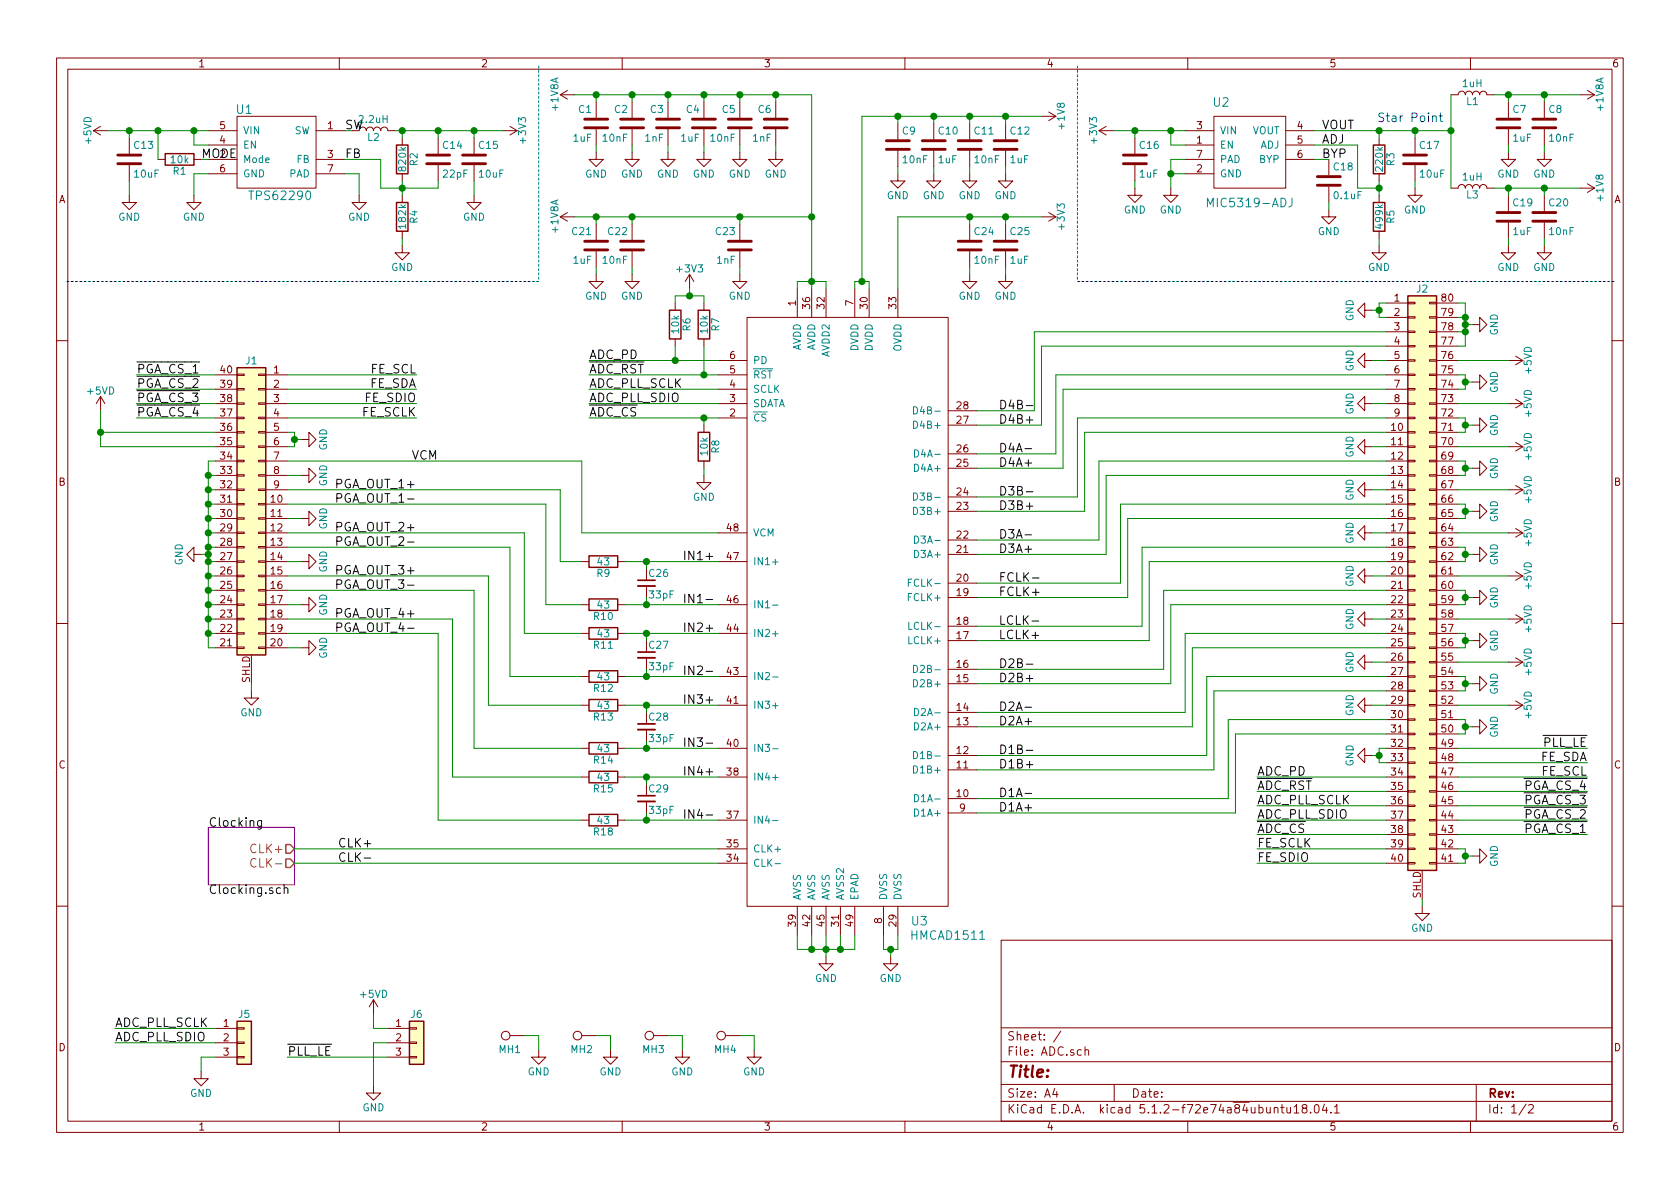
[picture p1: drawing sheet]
<svg xmlns="http://www.w3.org/2000/svg" width="297mm" height="210mm" viewBox="0 0 297 210" stroke-linecap="round" stroke-linejoin="round" font-family="sans-serif">
<defs><g id="words">
<text font-size="2.8" fill="#840000" x="178" y="190.5">Title:</text>
<g font-size="2.1" fill="#008484">
<text x="41.8" y="20.1">U1</text>
<text x="214.6" y="18.9">U2</text>
<text x="44.5" y="35.4">TPS62290</text>
<text x="214.2" y="36.6">MIC5319-ADJ</text>
<text x="161.2" y="163.6">U3</text>
<text x="161.3" y="166.2">HMCAD1511</text>
</g>
<g font-size="2.1" fill="#008400">
<text x="61" y="22.9">SW</text>
<text x="35.6" y="27.9">MODE</text>
</g>
<g font-size="2.1">
<text x="233.7" y="22.9">VOUT</text>
<text x="61" y="27.9">FB</text>
<text x="233.7" y="25.4">ADJ</text>
<text x="233.7" y="27.9">BYP</text>
<text x="104.1" y="63.5">ADC_PD</text>
<text x="24.1" y="66">PGA_CS_1</text>
<text x="24.1" y="68.6">PGA_CS_2</text>
<text x="24.1" y="71.1">PGA_CS_3</text>
<text x="64.6" y="71.1">FE_SDIO</text>
<text x="65.3" y="68.6">FE_SDA</text>
<text x="65.5" y="66">FE_SCL</text>
<text x="104.1" y="71.1">ADC_PLL_SDIO</text>
<text x="104.1" y="68.6">ADC_PLL_SCLK</text>
<text x="104.1" y="66">ADC_RST</text>
<text x="24.1" y="73.7">PGA_CS_4</text>
<text x="64" y="73.7">FE_SCLK</text>
<text x="104.1" y="73.7">ADC_CS</text>
<text x="176.5" y="72.4">D4B-</text>
<text x="176.5" y="74.9">D4B+</text>
<text x="72.7" y="81.3">VCM</text>
<text x="176.5" y="80">D4A-</text>
<text x="176.5" y="82.5">D4A+</text>
<text x="59.8" y="86.4">PGA_OUT_1+</text>
<text x="60.3" y="88.9">PGA_OUT_1-</text>
<text x="176.5" y="87.6">D3B-</text>
<text x="59.8" y="94">PGA_OUT_2+</text>
<text x="176.5" y="95.2">D3A-</text>
<text x="176.5" y="90.2">D3B+</text>
<text x="59.8" y="101.6">PGA_OUT_3+</text>
<text x="60.3" y="96.5">PGA_OUT_2-</text>
<text x="120.6" y="99.1">IN1+</text>
<text x="176.5" y="97.8">D3A+</text>
<text x="60.3" y="104.1">PGA_OUT_3-</text>
<text x="120.6" y="106.7">IN1-</text>
<text x="176.5" y="102.9">FCLK-</text>
<text x="176.5" y="105.4">FCLK+</text>
<text x="59.8" y="109.2">PGA_OUT_4+</text>
<text x="60.3" y="111.8">PGA_OUT_4-</text>
<text x="120.6" y="111.8">IN2+</text>
<text x="176.5" y="113">LCLK+</text>
<text x="176.5" y="110.5">LCLK-</text>
<text x="120.6" y="119.4">IN2-</text>
<text x="176.5" y="118.1">D2B-</text>
<text x="120.6" y="124.5">IN3+</text>
<text x="176.5" y="125.7">D2A-</text>
<text x="176.5" y="120.6">D2B+</text>
<text x="176.5" y="128.3">D2A+</text>
<text x="120.6" y="137.2">IN4+</text>
<text x="120.6" y="132.1">IN3-</text>
<text x="176.5" y="135.9">D1B+</text>
<text x="176.5" y="133.3">D1B-</text>
<text x="222.2" y="137.2">ADC_PD</text>
<text x="272.3" y="134.6">FE_SDA</text>
<text x="272.5" y="137.2">FE_SCL</text>
<text x="272.8" y="132.1">PLL_LE</text>
<text x="176.5" y="143.5">D1A+</text>
<text x="176.5" y="141">D1A-</text>
<text x="222.2" y="139.7">ADC_RST</text>
<text x="222.2" y="142.2">ADC_PLL_SCLK</text>
<text x="269.6" y="142.2">PGA_CS_3</text>
<text x="269.6" y="139.7">PGA_CS_4</text>
<text x="36.8" y="146.2">Clocking</text>
<text x="59.7" y="149.9">CLK+</text>
<text x="120.6" y="144.8">IN4-</text>
<text x="222.2" y="144.8">ADC_PLL_SDIO</text>
<text x="222.2" y="147.3">ADC_CS</text>
<text x="222.2" y="149.9">FE_SCLK</text>
<text x="269.6" y="147.3">PGA_CS_1</text>
<text x="269.6" y="144.8">PGA_CS_2</text>
<text x="59.7" y="152.4">CLK-</text>
<text x="222.2" y="152.4">FE_SDIO</text>
<text x="36.8" y="158.1">Clocking.sch</text>
<text x="20.3" y="184.1">ADC_PLL_SDIO</text>
<text x="20.3" y="181.6">ADC_PLL_SCLK</text>
<text x="50.8" y="186.7">PLL_LE</text>
</g>
<text font-size="2.1" fill="#0000c2" x="245.2" y="21.6">Star Point</text>
<g font-size="2.1" fill="#848400">
<text x="44.7" y="150.9">CLK+</text>
<text x="45.2" y="153.4">CLK-</text>
</g>
<g font-size="2.1" fill="#840000">
<text x="178" y="184">Sheet: /</text>
<text x="178" y="186.7">File: ADC.sch</text>
<text x="178" y="196.9">KiCad E.D.A. kicad 5.1.2-f72e74a84ubuntu18.04.1</text>
<text x="178" y="194.1">Size: A4</text>
<text x="200" y="194.1">Date:</text>
<text x="263" y="194.1">Rev:</text>
<text x="263" y="196.9">Id: 1/2</text>
</g>
<g font-size="1.8" fill="#840000">
<text x="35" y="11.9">1</text>
<text x="85" y="11.9">2</text>
<text x="135" y="11.9">3</text>
<text x="185" y="11.9">4</text>
<text x="235" y="11.9">5</text>
<text x="285" y="11.9">6</text>
<text x="38.9" y="22.9">5</text>
<text x="57.9" y="22.9">1</text>
<text x="211.6" y="22.9">3</text>
<text x="229.4" y="22.9">4</text>
<text x="38.9" y="25.4">4</text>
<text x="57.9" y="27.9">3</text>
<text x="211.6" y="25.4">1</text>
<text x="211.6" y="27.9">7</text>
<text x="229.4" y="25.4">5</text>
<text x="229.4" y="27.9">6</text>
<text x="10.4" y="35.9">A</text>
<text x="38.9" y="30.5">6</text>
<text x="57.9" y="30.5">7</text>
<text x="211.6" y="30.5">2</text>
<text x="285.4" y="35.9">A</text>
<text x="246.5" y="53.3">1</text>
<text x="254.9" y="53.3">80</text>
<text x="140.7" y="54.1" transform="rotate(-90 140.7 54.1)">1</text>
<text x="143.3" y="54.6" transform="rotate(-90 143.3 54.6)">36</text>
<text x="145.8" y="54.6" transform="rotate(-90 145.8 54.6)">32</text>
<text x="150.9" y="54.1" transform="rotate(-90 150.9 54.1)">7</text>
<text x="153.4" y="54.6" transform="rotate(-90 153.4 54.6)">30</text>
<text x="158.5" y="54.6" transform="rotate(-90 158.5 54.6)">33</text>
<text x="246.5" y="55.9">2</text>
<text x="246.5" y="58.4">3</text>
<text x="254.9" y="58.4">78</text>
<text x="254.9" y="55.9">79</text>
<text x="129.1" y="63.5">6</text>
<text x="246.5" y="61">4</text>
<text x="246.5" y="63.5">5</text>
<text x="254.9" y="63.5">76</text>
<text x="254.9" y="61">77</text>
<text x="39" y="71.1">38</text>
<text x="39" y="68.6">39</text>
<text x="39" y="66">40</text>
<text x="48.4" y="66">1</text>
<text x="48.4" y="68.6">2</text>
<text x="48.4" y="71.1">3</text>
<text x="129.1" y="71.1">3</text>
<text x="129.1" y="68.6">4</text>
<text x="129.1" y="66">5</text>
<text x="246.5" y="66">6</text>
<text x="246.5" y="68.6">7</text>
<text x="246.5" y="71.1">8</text>
<text x="254.9" y="71.1">73</text>
<text x="254.9" y="68.6">74</text>
<text x="254.9" y="66">75</text>
<text x="39" y="76.2">36</text>
<text x="39" y="73.7">37</text>
<text x="48.4" y="73.7">4</text>
<text x="48.4" y="76.2">5</text>
<text x="129.1" y="73.7">2</text>
<text x="169.2" y="74.9">27</text>
<text x="169.2" y="72.4">28</text>
<text x="246" y="76.2">10</text>
<text x="246.5" y="73.7">9</text>
<text x="254.9" y="76.2">71</text>
<text x="254.9" y="73.7">72</text>
<text x="39" y="83.8">33</text>
<text x="39" y="81.3">34</text>
<text x="39" y="78.7">35</text>
<text x="48.4" y="78.7">6</text>
<text x="48.4" y="81.3">7</text>
<text x="48.4" y="83.8">8</text>
<text x="169.2" y="82.5">25</text>
<text x="169.2" y="80">26</text>
<text x="246" y="78.7">11</text>
<text x="246" y="81.3">12</text>
<text x="246" y="83.8">13</text>
<text x="254.9" y="83.8">68</text>
<text x="254.9" y="81.3">69</text>
<text x="254.9" y="78.7">70</text>
<text x="10.4" y="85.9">B</text>
<text x="39" y="88.9">31</text>
<text x="39" y="86.4">32</text>
<text x="47.9" y="88.9">10</text>
<text x="48.4" y="86.4">9</text>
<text x="169.2" y="87.6">24</text>
<text x="246" y="86.4">14</text>
<text x="246" y="88.9">15</text>
<text x="254.9" y="88.9">66</text>
<text x="254.9" y="86.4">67</text>
<text x="285.4" y="85.9">B</text>
<text x="39" y="94">29</text>
<text x="39" y="91.4">30</text>
<text x="47.9" y="91.4">11</text>
<text x="47.9" y="94">12</text>
<text x="128.6" y="94">48</text>
<text x="169.2" y="95.2">22</text>
<text x="169.2" y="90.2">23</text>
<text x="246" y="91.4">16</text>
<text x="246" y="94">17</text>
<text x="254.9" y="94">64</text>
<text x="254.9" y="91.4">65</text>
<text x="39" y="101.6">26</text>
<text x="39" y="99.1">27</text>
<text x="39" y="96.5">28</text>
<text x="47.9" y="96.5">13</text>
<text x="47.9" y="99.1">14</text>
<text x="47.9" y="101.6">15</text>
<text x="128.6" y="99.1">47</text>
<text x="169.2" y="97.8">21</text>
<text x="246" y="96.5">18</text>
<text x="246" y="99.1">19</text>
<text x="246" y="101.6">20</text>
<text x="254.9" y="101.6">61</text>
<text x="254.9" y="99.1">62</text>
<text x="254.9" y="96.5">63</text>
<text x="39" y="106.7">24</text>
<text x="39" y="104.1">25</text>
<text x="47.9" y="104.1">16</text>
<text x="47.9" y="106.7">17</text>
<text x="128.6" y="106.7">46</text>
<text x="169.2" y="105.4">19</text>
<text x="169.2" y="102.9">20</text>
<text x="246" y="104.1">21</text>
<text x="246" y="106.7">22</text>
<text x="254.9" y="106.7">59</text>
<text x="254.9" y="104.1">60</text>
<text x="39" y="111.8">22</text>
<text x="39" y="109.2">23</text>
<text x="47.9" y="109.2">18</text>
<text x="47.9" y="111.8">19</text>
<text x="128.6" y="111.8">44</text>
<text x="169.2" y="113">17</text>
<text x="169.2" y="110.5">18</text>
<text x="246" y="109.2">23</text>
<text x="246" y="111.8">24</text>
<text x="254.9" y="111.8">57</text>
<text x="254.9" y="109.2">58</text>
<text x="39" y="114.3">21</text>
<text x="47.9" y="114.3">20</text>
<text x="128.6" y="119.4">43</text>
<text x="169.2" y="118.1">16</text>
<text x="246" y="114.3">25</text>
<text x="246" y="116.8">26</text>
<text x="246" y="119.4">27</text>
<text x="254.9" y="119.4">54</text>
<text x="254.9" y="116.8">55</text>
<text x="254.9" y="114.3">56</text>
<text x="44.2" y="120.8" transform="rotate(-90 44.2 120.8)">SHLD</text>
<text x="128.6" y="124.5">41</text>
<text x="169.2" y="125.7">14</text>
<text x="169.2" y="120.6">15</text>
<text x="246" y="121.9">28</text>
<text x="246" y="124.5">29</text>
<text x="254.9" y="124.5">52</text>
<text x="254.9" y="121.9">53</text>
<text x="169.2" y="128.3">13</text>
<text x="246" y="127">30</text>
<text x="246" y="129.5">31</text>
<text x="254.9" y="129.5">50</text>
<text x="254.9" y="127">51</text>
<text x="10.4" y="135.9">C</text>
<text x="128.6" y="137.2">38</text>
<text x="128.6" y="132.1">40</text>
<text x="169.2" y="135.9">11</text>
<text x="169.2" y="133.3">12</text>
<text x="246" y="132.1">32</text>
<text x="246" y="134.6">33</text>
<text x="246" y="137.2">34</text>
<text x="254.9" y="137.2">47</text>
<text x="254.9" y="134.6">48</text>
<text x="254.9" y="132.1">49</text>
<text x="285.4" y="135.9">C</text>
<text x="169.2" y="141">10</text>
<text x="169.7" y="143.5">9</text>
<text x="246" y="139.7">35</text>
<text x="246" y="142.2">36</text>
<text x="254.9" y="142.2">45</text>
<text x="254.9" y="139.7">46</text>
<text x="128.6" y="149.9">35</text>
<text x="128.6" y="144.8">37</text>
<text x="246" y="144.8">37</text>
<text x="246" y="147.3">38</text>
<text x="246" y="149.9">39</text>
<text x="254.9" y="149.9">42</text>
<text x="254.9" y="147.3">43</text>
<text x="254.9" y="144.8">44</text>
<text x="128.6" y="152.4">34</text>
<text x="246" y="152.4">40</text>
<text x="254.9" y="152.4">41</text>
<text x="251.2" y="158.9" transform="rotate(-90 251.2 158.9)">SHLD</text>
<text x="140.7" y="163.8" transform="rotate(-90 140.7 163.8)">39</text>
<text x="143.3" y="163.8" transform="rotate(-90 143.3 163.8)">42</text>
<text x="145.8" y="163.8" transform="rotate(-90 145.8 163.8)">45</text>
<text x="148.3" y="163.8" transform="rotate(-90 148.3 163.8)">31</text>
<text x="150.9" y="163.8" transform="rotate(-90 150.9 163.8)">49</text>
<text x="156" y="163.3" transform="rotate(-90 156 163.3)">8</text>
<text x="158.5" y="163.8" transform="rotate(-90 158.5 163.8)">29</text>
<text x="10.4" y="185.9">D</text>
<text x="39.5" y="181.6">1</text>
<text x="39.5" y="184.1">2</text>
<text x="70" y="181.6">1</text>
<text x="70" y="184.1">2</text>
<text x="285.4" y="185.9">D</text>
<text x="39.5" y="186.7">3</text>
<text x="70" y="186.7">3</text>
<text x="35" y="199.9">1</text>
<text x="85" y="199.9">2</text>
<text x="135" y="199.9">3</text>
<text x="185" y="199.9">4</text>
<text x="235" y="199.9">5</text>
<text x="285" y="199.9">6</text>
</g>
<g font-size="1.8" fill="#008484">
<text x="258.6" y="15.4">1uH</text>
<text x="42.9" y="23.7">VIN</text>
<text x="52" y="23.7">SW</text>
<text x="63.6" y="21.8">2.2uH</text>
<text x="98.7" y="19.5" transform="rotate(-90 98.7 19.5)">+1V8A</text>
<text x="102.3" y="20">C1</text>
<text x="108.7" y="20">C2</text>
<text x="115" y="20">C3</text>
<text x="121.4" y="20">C4</text>
<text x="127.7" y="20">C5</text>
<text x="134.1" y="20">C6</text>
<text x="159.6" y="23.8">C9</text>
<text x="166" y="23.8">C10</text>
<text x="172.4" y="23.8">C11</text>
<text x="178.7" y="23.8">C12</text>
<text x="188.3" y="22.7" transform="rotate(-90 188.3 22.7)">+1V8</text>
<text x="215.6" y="23.7">VIN</text>
<text x="221.4" y="23.7">VOUT</text>
<text x="259.3" y="18.6">L1</text>
<text x="267.5" y="20">C7</text>
<text x="273.9" y="20">C8</text>
<text x="283.5" y="19.5" transform="rotate(-90 283.5 19.5)">+1V8A</text>
<text x="16.2" y="25.3" transform="rotate(-90 16.2 25.3)">+5VD</text>
<text x="23.8" y="26.3">C13</text>
<text x="30.3" y="28.9">10k</text>
<text x="42.9" y="28.8">Mode</text>
<text x="42.9" y="26.3">EN</text>
<text x="52.5" y="28.8">FB</text>
<text x="65" y="24.9">L2</text>
<text x="73.8" y="29.3" transform="rotate(-90 73.8 29.3)">R2</text>
<text x="78.4" y="26.3">C14</text>
<text x="84.7" y="26.3">C15</text>
<text x="93" y="25.2" transform="rotate(-90 93 25.2)">+3V3</text>
<text x="101.4" y="25.1">1uF</text>
<text x="106.7" y="25.1">10nF</text>
<text x="114.1" y="25.1">1nF</text>
<text x="120.4" y="25.1">1uF</text>
<text x="125.7" y="25.1">10nF</text>
<text x="133.1" y="25.1">1nF</text>
<text x="159.7" y="28.9">10nF</text>
<text x="166" y="28.9">1uF</text>
<text x="172.4" y="28.9">10nF</text>
<text x="178.7" y="28.9">1uF</text>
<text x="194" y="25.2" transform="rotate(-90 194 25.2)">+3V3</text>
<text x="201.6" y="26.3">C16</text>
<text x="215.6" y="26.3">EN</text>
<text x="215.6" y="28.8">PAD</text>
<text x="222.7" y="28.8">BYP</text>
<text x="222.8" y="26.3">ADJ</text>
<text x="246.6" y="29.3" transform="rotate(-90 246.6 29.3)">R3</text>
<text x="251.1" y="26.3">C17</text>
<text x="267.6" y="25.1">1uF</text>
<text x="274" y="25.1">10nF</text>
<text x="23.8" y="31.4">10uF</text>
<text x="30.6" y="30.9">R1</text>
<text x="42.9" y="31.4">GND</text>
<text x="51.1" y="31.4">PAD</text>
<text x="71.8" y="30.1" transform="rotate(-90 71.8 30.1)">820k</text>
<text x="78.4" y="31.4">22pF</text>
<text x="84.8" y="31.4">10uF</text>
<text x="103.5" y="31.4">GND</text>
<text x="109.8" y="31.4">GND</text>
<text x="116.2" y="31.4">GND</text>
<text x="122.5" y="31.4">GND</text>
<text x="128.9" y="31.4">GND</text>
<text x="135.2" y="31.4">GND</text>
<text x="156.8" y="35.2">GND</text>
<text x="163.1" y="35.2">GND</text>
<text x="169.5" y="35.2">GND</text>
<text x="175.8" y="35.2">GND</text>
<text x="201.5" y="31.4">1uF</text>
<text x="215.6" y="31.4">GND</text>
<text x="235.9" y="30.1">C18</text>
<text x="236" y="35.2">0.1uF</text>
<text x="244.5" y="30.1" transform="rotate(-90 244.5 30.1)">220k</text>
<text x="251.2" y="31.4">10uF</text>
<text x="258.6" y="31.9">1uH</text>
<text x="259.3" y="35.1">L3</text>
<text x="264.7" y="31.4">GND</text>
<text x="271.1" y="31.4">GND</text>
<text x="283.5" y="35.4" transform="rotate(-90 283.5 35.4)">+1V8</text>
<text x="20.9" y="39">GND</text>
<text x="32.3" y="39">GND</text>
<text x="61.5" y="39">GND</text>
<text x="71.8" y="40.3" transform="rotate(-90 71.8 40.3)">182k</text>
<text x="73.8" y="39.5" transform="rotate(-90 73.8 39.5)">R4</text>
<text x="81.9" y="39">GND</text>
<text x="98.7" y="41" transform="rotate(-90 98.7 41)">+1V8A</text>
<text x="101.2" y="41.6">C21</text>
<text x="107.6" y="41.6">C22</text>
<text x="126.6" y="41.6">C23</text>
<text x="172.4" y="41.6">C24</text>
<text x="178.7" y="41.6">C25</text>
<text x="188.3" y="40.4" transform="rotate(-90 188.3 40.4)">+3V3</text>
<text x="198.7" y="37.8">GND</text>
<text x="205.1" y="37.8">GND</text>
<text x="233" y="41.6">GND</text>
<text x="244.5" y="40.3" transform="rotate(-90 244.5 40.3)">499k</text>
<text x="246.6" y="39.5" transform="rotate(-90 246.6 39.5)">R5</text>
<text x="248.2" y="37.8">GND</text>
<text x="267.6" y="41.6">1uF</text>
<text x="267.6" y="36.5">C19</text>
<text x="274" y="36.5">C20</text>
<text x="274" y="41.6">10nF</text>
<text x="69.2" y="47.9">GND</text>
<text x="101.4" y="46.7">1uF</text>
<text x="106.7" y="46.7">10nF</text>
<text x="126.8" y="46.7">1nF</text>
<text x="172.4" y="46.7">10nF</text>
<text x="178.7" y="46.7">1uF</text>
<text x="241.9" y="47.9">GND</text>
<text x="264.7" y="47.9">GND</text>
<text x="271.1" y="47.9">GND</text>
<text x="103.5" y="53">GND</text>
<text x="109.8" y="53">GND</text>
<text x="119.8" y="48.2">+3V3</text>
<text x="128.9" y="53">GND</text>
<text x="169.5" y="53">GND</text>
<text x="175.8" y="53">GND</text>
<text x="250.5" y="51.7">J2</text>
<text x="120.1" y="58.9" transform="rotate(-90 120.1 58.9)">10k</text>
<text x="122.1" y="58.5" transform="rotate(-90 122.1 58.5)">R6</text>
<text x="125.1" y="58.9" transform="rotate(-90 125.1 58.9)">10k</text>
<text x="127.2" y="58.5" transform="rotate(-90 127.2 58.5)">R7</text>
<text x="239.3" y="56.8" transform="rotate(-90 239.3 56.8)">GND</text>
<text x="264.8" y="59.4" transform="rotate(-90 264.8 59.4)">GND</text>
<text x="43.5" y="64.4">J1</text>
<text x="133.1" y="64.4">PD</text>
<text x="141.6" y="62.1" transform="rotate(-90 141.6 62.1)">AVDD</text>
<text x="144.1" y="62.1" transform="rotate(-90 144.1 62.1)">AVDD</text>
<text x="146.7" y="63.1" transform="rotate(-90 146.7 63.1)">AVDD2</text>
<text x="151.8" y="62.1" transform="rotate(-90 151.8 62.1)">DVDD</text>
<text x="154.3" y="62.1" transform="rotate(-90 154.3 62.1)">DVDD</text>
<text x="159.4" y="62.2" transform="rotate(-90 159.4 62.2)">OVDD</text>
<text x="239.3" y="65.7" transform="rotate(-90 239.3 65.7)">GND</text>
<text x="270.8" y="66" transform="rotate(-90 270.8 66)">+5VD</text>
<text x="15.5" y="69.8">+5VD</text>
<text x="133.1" y="69.5">SCLK</text>
<text x="133.1" y="66.9">RST</text>
<text x="264.8" y="69.5" transform="rotate(-90 264.8 69.5)">GND</text>
<text x="133.1" y="74.5">CS</text>
<text x="133.1" y="72">SDATA</text>
<text x="162.1" y="75.8">D4B+</text>
<text x="162.5" y="73.3">D4B-</text>
<text x="239.3" y="73.3" transform="rotate(-90 239.3 73.3)">GND</text>
<text x="264.8" y="77.1" transform="rotate(-90 264.8 77.1)">GND</text>
<text x="270.8" y="73.6" transform="rotate(-90 270.8 73.6)">+5VD</text>
<text x="57.8" y="79.7" transform="rotate(-90 57.8 79.7)">GND</text>
<text x="125.1" y="80.5" transform="rotate(-90 125.1 80.5)">10k</text>
<text x="127.2" y="80.1" transform="rotate(-90 127.2 80.1)">R8</text>
<text x="162.1" y="83.4">D4A+</text>
<text x="162.5" y="80.9">D4A-</text>
<text x="239.3" y="80.9" transform="rotate(-90 239.3 80.9)">GND</text>
<text x="270.8" y="81.2" transform="rotate(-90 270.8 81.2)">+5VD</text>
<text x="57.8" y="86" transform="rotate(-90 57.8 86)">GND</text>
<text x="122.5" y="88.6">GND</text>
<text x="162.5" y="88.5">D3B-</text>
<text x="239.3" y="88.6" transform="rotate(-90 239.3 88.6)">GND</text>
<text x="264.8" y="84.8" transform="rotate(-90 264.8 84.8)">GND</text>
<text x="270.8" y="88.8" transform="rotate(-90 270.8 88.8)">+5VD</text>
<text x="57.8" y="93.6" transform="rotate(-90 57.8 93.6)">GND</text>
<text x="133.1" y="94.9">VCM</text>
<text x="162.1" y="91.1">D3B+</text>
<text x="264.8" y="92.4" transform="rotate(-90 264.8 92.4)">GND</text>
<text x="32.3" y="100" transform="rotate(-90 32.3 100)">GND</text>
<text x="57.8" y="101.3" transform="rotate(-90 57.8 101.3)">GND</text>
<text x="105.7" y="100">43</text>
<text x="133.1" y="99.9">IN1+</text>
<text x="162.1" y="98.7">D3A+</text>
<text x="162.5" y="96.1">D3A-</text>
<text x="239.3" y="96.2" transform="rotate(-90 239.3 96.2)">GND</text>
<text x="264.8" y="100" transform="rotate(-90 264.8 100)">GND</text>
<text x="270.8" y="96.5" transform="rotate(-90 270.8 96.5)">+5VD</text>
<text x="105.6" y="102">R9</text>
<text x="105.7" y="107.6">43</text>
<text x="114.8" y="102">C26</text>
<text x="114.9" y="105.8">33pF</text>
<text x="133.1" y="107.6">IN1-</text>
<text x="160.9" y="106.3">FCLK+</text>
<text x="161.3" y="103.8">FCLK-</text>
<text x="239.3" y="103.8" transform="rotate(-90 239.3 103.8)">GND</text>
<text x="264.8" y="107.6" transform="rotate(-90 264.8 107.6)">GND</text>
<text x="270.8" y="104.1" transform="rotate(-90 270.8 104.1)">+5VD</text>
<text x="57.8" y="108.9" transform="rotate(-90 57.8 108.9)">GND</text>
<text x="105.1" y="109.6">R10</text>
<text x="105.7" y="112.7">43</text>
<text x="133.1" y="112.6">IN2+</text>
<text x="160.9" y="113.9">LCLK+</text>
<text x="161.3" y="111.4">LCLK-</text>
<text x="239.3" y="111.4" transform="rotate(-90 239.3 111.4)">GND</text>
<text x="270.8" y="111.7" transform="rotate(-90 270.8 111.7)">+5VD</text>
<text x="57.8" y="116.5" transform="rotate(-90 57.8 116.5)">GND</text>
<text x="105.1" y="114.7">R11</text>
<text x="114.8" y="114.7">C27</text>
<text x="114.9" y="118.5">33pF</text>
<text x="162.5" y="119">D2B-</text>
<text x="239.3" y="119" transform="rotate(-90 239.3 119)">GND</text>
<text x="264.8" y="115.2" transform="rotate(-90 264.8 115.2)">GND</text>
<text x="270.8" y="119.3" transform="rotate(-90 270.8 119.3)">+5VD</text>
<text x="105.1" y="122.3">R12</text>
<text x="105.7" y="120.3">43</text>
<text x="105.7" y="125.4">43</text>
<text x="133.1" y="125.3">IN3+</text>
<text x="133.1" y="120.3">IN2-</text>
<text x="162.1" y="121.5">D2B+</text>
<text x="264.8" y="122.9" transform="rotate(-90 264.8 122.9)">GND</text>
<text x="42.5" y="126.7">GND</text>
<text x="105.1" y="127.4">R13</text>
<text x="114.8" y="127.4">C28</text>
<text x="114.9" y="131.2">33pF</text>
<text x="162.1" y="129.2">D2A+</text>
<text x="162.5" y="126.6">D2A-</text>
<text x="239.3" y="126.7" transform="rotate(-90 239.3 126.7)">GND</text>
<text x="264.8" y="130.5" transform="rotate(-90 264.8 130.5)">GND</text>
<text x="270.8" y="126.9" transform="rotate(-90 270.8 126.9)">+5VD</text>
<text x="105.1" y="135">R14</text>
<text x="105.7" y="133">43</text>
<text x="133.1" y="133">IN3-</text>
<text x="162.1" y="136.8">D1B+</text>
<text x="162.5" y="134.2">D1B-</text>
<text x="239.3" y="135.6" transform="rotate(-90 239.3 135.6)">GND</text>
<text x="105.1" y="140.1">R15</text>
<text x="105.7" y="138.1">43</text>
<text x="114.8" y="140.1">C29</text>
<text x="114.9" y="143.9">33pF</text>
<text x="133.1" y="138">IN4+</text>
<text x="162.5" y="141.9">D1A-</text>
<text x="105.1" y="147.7">R18</text>
<text x="105.7" y="145.7">43</text>
<text x="133.1" y="145.7">IN4-</text>
<text x="162.1" y="144.4">D1A+</text>
<text x="133.1" y="153.3">CLK-</text>
<text x="133.1" y="150.7">CLK+</text>
<text x="264.8" y="153.3" transform="rotate(-90 264.8 153.3)">GND</text>
<text x="141.6" y="159.3" transform="rotate(-90 141.6 159.3)">AVSS</text>
<text x="144.1" y="159.3" transform="rotate(-90 144.1 159.3)">AVSS</text>
<text x="146.7" y="159.3" transform="rotate(-90 146.7 159.3)">AVSS</text>
<text x="149.2" y="159.3" transform="rotate(-90 149.2 159.3)">AVSS2</text>
<text x="151.8" y="159.3" transform="rotate(-90 151.8 159.3)">EPAD</text>
<text x="156.8" y="159.3" transform="rotate(-90 156.8 159.3)">DVSS</text>
<text x="159.4" y="159.3" transform="rotate(-90 159.4 159.3)">DVSS</text>
<text x="249.5" y="164.8">GND</text>
<text x="144.1" y="173.7">GND</text>
<text x="155.5" y="173.7">GND</text>
<text x="63.8" y="176.4">+5VD</text>
<text x="42.2" y="180">J5</text>
<text x="72.7" y="180">J6</text>
<text x="88.3" y="186.2">MH1</text>
<text x="93.3" y="190.2">GND</text>
<text x="101" y="186.2">MH2</text>
<text x="106" y="190.2">GND</text>
<text x="113.7" y="186.2">MH3</text>
<text x="118.7" y="190.2">GND</text>
<text x="126.4" y="186.2">MH4</text>
<text x="131.4" y="190.2">GND</text>
<text x="33.6" y="194">GND</text>
<text x="64.1" y="196.5">GND</text>
</g>
<text font-size="1.8" x="38.9" y="27.9">2</text>
</g></defs>
<g fill="none" stroke="#840000" stroke-width=".18">
<path d="M10 10.3h277v189.9h-277zM12 12.2h273v186.1h-273zM60 10.3v1.9M99.1 16.8l1.2 .7M99.1 16.8h2.5M100.3 16l-1.2 .8M105.4 18v2.8M110 10.3v1.9M111.8 18v2.8M118.1 18v2.8M124.5 18v2.8M130.8 18v2.8"/>
<path d="M137.2 18v2.8M160 10.3v1.9M185.4 19.8l1.3 .8M210 10.3v1.9M256.5 16.8h1.3a.63 .63 0 0 1 .6-.7 .63 .63 0 0 1 .7 .7 .63 .63 0 0 1 .6-.7 .63 .63 0 0 1 .6 .7 .63 .63 0 0 1 .7-.7 .63 .63 0 0 1 .6 .7 .63 .63 0 0 1 .7-.7 .63 .63 0 0 1 .6 .7h1.3M260 10.3v1.9M266.7 18v2.8M273 18v2.8M279.4 16.8h2.5M280.7 16l1.2 .8M281.9 16.8l-1.2 .7M16.5 23.1h2.5"/>
<path d="M16.5 23.1l1.3 .8M17.8 22.3l-1.3 .8M22.9 34.5v1.3h1.2l-1.2 1.3-1.3-1.3h1.3M22.9 24.4v2.8M22.9 29.2v2.8M27.9 28.2h1.3M34.3 34.5v1.3h1.3l-1.3 1.3-1.3-1.3h1.3M34.3 28.2h1.3M36.8 25.6h5.1M36.8 30.7h5.1M36.8 23.1h5.1M36.8 28.2h5.1"/>
<path d="M41.9 20.6h14v12.7h-14zM55.9 30.7h5.1M55.9 23.1h5.1M55.9 28.2h5.1M63.5 34.5v1.3h1.3l-1.3 1.3-1.3-1.3h1.3M64.8 23.1a.63 .63 0 0 1 .6-.6 .63 .63 0 0 1 .6 .6 .63 .63 0 0 1 .7-.6 .63 .63 0 0 1 .6 .6 .63 .63 0 0 1 .6-.6 .63 .63 0 0 1 .7 .6h1.2M71.1 24.4v1.2M71.1 30.7v1.3M71.1 34.5v1.3M77.5 24.4v2.8M77.5 29.2v2.8M83.8 34.5v1.3h1.3l-1.3 1.3-1.3-1.3h1.3"/>
<path d="M83.8 24.4v2.8M83.8 29.2v2.8M88.9 23.1h2.5M90.2 22.3l1.2 .8M91.4 23.1l-1.2 .8M99.1 38.3h2.5M99.1 38.3l1.2 .8M100.3 37.6l-1.2 .7M105.4 26.9v1.3h-1.3l1.3 1.3 1.3-1.3h-1.3M105.4 22.9v2.7M105.4 39.6v2.8M111.8 26.9v1.3h-1.3l1.3 1.3 1.2-1.3h-1.2"/>
<path d="M111.8 22.9v2.7M111.8 39.6v2.8M118.1 26.9v1.3h-1.3l1.3 1.3 1.3-1.3h-1.3M118.1 22.9v2.7M124.5 26.9v1.3h-1.3l1.3 1.3 1.2-1.3h-1.2M124.5 22.9v2.7M130.8 26.9v1.3h-1.3l1.3 1.3 1.3-1.3h-1.3M130.8 22.9v2.7M130.8 39.6v2.8M137.2 26.9v1.3h-1.3l1.3 1.3 1.2-1.3h-1.2M137.2 22.9v2.7M158.7 30.7v1.3h1.3l-1.3 1.3-1.2-1.3h1.2"/>
<path d="M158.7 21.8v2.8M158.7 26.7v2.8M165.1 30.7v1.3h1.3l-1.3 1.3-1.3-1.3h1.3M165.1 21.8v2.8M165.1 26.7v2.8M171.4 30.7v1.3h1.3l-1.3 1.3-1.2-1.3h1.2M171.4 21.8v2.8M171.4 26.7v2.8M171.4 39.6v2.8M177.8 30.7v1.3h1.3l-1.3 1.3-1.3-1.3h1.3M177.8 21.8v2.8M177.8 26.7v2.8"/>
<path d="M177.8 39.6v2.8M184.1 38.3h2.6M184.1 20.6h2.6M185.4 37.6l1.3 .7M186.7 38.3l-1.3 .8M186.7 20.6l-1.3 .7M194.3 23.1h2.5M194.3 23.1l1.3 .8M195.6 22.3l-1.3 .8M200.7 33.3v1.2h1.2l-1.2 1.3-1.3-1.3h1.3M200.7 24.4v2.8M200.7 29.2v2.8"/>
<path d="M207 33.3v1.2h1.3l-1.3 1.3-1.3-1.3h1.3M209.5 25.6h5.1M209.5 30.7h5.1M209.5 23.1h5.1M209.5 28.2h5.1M214.6 20.6h12.7v12.7h-12.7zM227.3 25.6h5.1M227.3 23.1h5.1M227.3 28.2h5.1M234.9 37.1v1.2h1.3l-1.3 1.3-1.2-1.3h1.2M234.9 28.2v2.8M234.9 33v2.8"/>
<path d="M243.8 24.4v1.2M243.8 30.7v1.3M243.8 34.5v1.3M250.2 33.3v1.2h1.3l-1.3 1.3-1.3-1.3h1.3M250.2 24.4v2.8M250.2 29.2v2.8M256.5 33.3h1.3a.63 .63 0 0 1 .6-.7 .63 .63 0 0 1 .7 .7 .63 .63 0 0 1 .6-.7 .63 .63 0 0 1 .6 .7 .63 .63 0 0 1 .7-.7 .63 .63 0 0 1 .6 .7 .63 .63 0 0 1 .7-.7 .63 .63 0 0 1 .6 .7h1.3M266.7 26.9v1.3h1.3l-1.3 1.3-1.3-1.3h1.3M266.7 22.9v2.7M266.7 34.5v2.8M266.7 39.4v2.8M273 26.9v1.3h1.3l-1.3 1.3-1.2-1.3h1.2"/>
<path d="M273 22.9v2.7M273 34.5v2.8M273 39.4v2.8M279.4 33.3h2.5M280.7 32.5l1.2 .8M281.9 33.3l-1.2 .7M71.1 43.4v1.3h1.3l-1.3 1.3-1.3-1.3h1.3M71.1 40.9v1.3M105.4 48.5v1.3h-1.3l1.3 1.2 1.3-1.2h-1.3M105.4 44.4v2.8M111.8 48.5v1.3h-1.3l1.3 1.2 1.2-1.2h-1.2M111.8 44.4v2.8"/>
<path d="M119.4 53.6v1.3M119.4 59.9v1.3M121.9 48.5l-.7 1.3M121.9 48.5v2.5M121.9 48.5l.8 1.3M124.5 53.6v1.3M124.5 59.9v1.3M130.8 48.5v1.3h-1.3l1.3 1.2 1.3-1.2h-1.3M130.8 44.4v2.8M132.1 56.1h35.5v104.2h-35.5zM141 51v5.1M143.5 51v5.1"/>
<path d="M146 51v5.1M151.1 51v5.1M153.7 51v5.1M158.7 51v5.1M171.4 48.5v1.3h1.3l-1.3 1.2-1.2-1.2h1.2M171.4 44.4v2.8M177.8 48.5v1.3h1.3l-1.3 1.2-1.3-1.2h1.3M177.8 44.4v2.8M241.3 54.9v-1.3l-1.3 1.3 1.3 1.2v-1.2h1.3M243.8 43.4v1.3h1.3l-1.3 1.3-1.2-1.3h1.2M243.8 40.9v1.3M245.1 53.6h3.8"/>
<path d="M245.1 56.1h3.8M245.1 58.7h3.8M248.9 58.5h1.3v.3h-1.3zM248.9 56h1.3v.3h-1.3zM248.9 53.5h1.3v.2h-1.3zM252.7 58.5h1.3v.3h-1.3zM252.7 56h1.3v.3h-1.3zM252.7 53.5h1.3v.2h-1.3zM254 53.6h3.8M254 56.1h3.8M254 58.7h3.8M260.3 57.4h1.3v1.3l1.3-1.3-1.3-1.3v1.3"/>
<path d="M266.7 43.4v1.3h1.3l-1.3 1.3-1.3-1.3h1.3M273 43.4v1.3h1.3l-1.3 1.3-1.2-1.3h1.2M10 60.2h2M17.8 70.1l.7 1.3M17.8 70.1v2.5M17.8 70.1l-.8 1.3M38.1 66.3h3.8M38.1 68.8h3.8M38.1 71.4h3.8M38.1 79h3.8M38.1 76.4h3.8M38.1 73.9h3.8"/>
<path d="M41.9 78.9h1.3v.2h-1.3zM41.9 76.3h1.3v.3h-1.3zM41.9 73.8h1.3v.2h-1.3zM41.9 71.2h1.3v.3h-1.3zM41.9 68.7h1.3v.3h-1.3zM41.9 66.2h1.3v.2h-1.3zM45.7 78.9h1.3v.2h-1.3zM45.7 76.3h1.3v.3h-1.3zM45.7 73.8h1.3v.2h-1.3zM45.7 71.2h1.3v.3h-1.3zM45.7 68.7h1.3v.3h-1.3zM45.7 66.2h1.3v.2h-1.3z"/>
<path d="M47 66.3h3.8M47 68.8h3.8M47 71.4h3.8M47 79h3.8M47 76.4h3.8M47 73.9h3.8M53.3 77.7h1.3v1.3l1.3-1.3-1.3-1.3v1.3M124.5 75.2v1.2M127 66.3h5.1M127 68.8h5.1M127 71.4h5.1M127 73.9h5.1"/>
<path d="M127 63.7h5.1M167.6 75.2h5.1M167.6 72.6h5.1M241.3 63.7v-1.2l-1.3 1.2 1.3 1.3v-1.3h1.3M241.3 71.4v-1.3l-1.3 1.3 1.3 1.2v-1.2h1.3M241.3 79v-1.3l-1.3 1.3 1.3 1.3v-1.3h1.3M245.1 66.3h3.8M245.1 68.8h3.8M245.1 71.4h3.8M245.1 79h3.8M245.1 76.4h3.8M245.1 73.9h3.8"/>
<path d="M245.1 61.2h3.8M245.1 63.7h3.8M248.9 78.9h1.3v.2h-1.3zM248.9 76.3h1.3v.3h-1.3zM248.9 73.8h1.3v.2h-1.3zM248.9 71.2h1.3v.3h-1.3zM248.9 68.7h1.3v.3h-1.3zM248.9 66.2h1.3v.2h-1.3zM248.9 63.6h1.3v.3h-1.3zM248.9 61.1h1.3v.2h-1.3zM252.7 78.9h1.3v.2h-1.3zM252.7 76.3h1.3v.3h-1.3z"/>
<path d="M252.7 73.8h1.3v.2h-1.3zM252.7 71.2h1.3v.3h-1.3zM252.7 68.7h1.3v.3h-1.3zM252.7 66.2h1.3v.2h-1.3zM252.7 63.6h1.3v.3h-1.3zM252.7 61.1h1.3v.2h-1.3zM254 66.3h3.8M254 68.8h3.8M254 71.4h3.8M254 79h3.8M254 76.4h3.8M254 73.9h3.8"/>
<path d="M254 61.2h3.8M254 63.7h3.8M260.3 67.6h1.3v1.2l1.3-1.2-1.3-1.3v1.3M260.3 75.2h1.3v1.2l1.3-1.2-1.3-1.3v1.3M266.7 71.4h2.5M266.7 79h2.5M266.7 63.7h2.5M268 63l1.2 .7M268 70.6l1.2 .8M268 78.2l1.2 .8M269.2 63.7l-1.2 .8M269.2 71.4l-1.2 .7"/>
<path d="M269.2 79l-1.2 .8M285 60.2h2M34.3 98v1.3l-1.3-1.3 1.3-1.2v1.2h1.3M38.1 89.1h3.8M38.1 91.7h3.8M38.1 94.2h3.8M38.1 96.8h3.8M38.1 99.3h3.8M38.1 86.6h3.8M38.1 84.1h3.8M38.1 81.5h3.8M41.9 99.2h1.3v.2h-1.3z"/>
<path d="M41.9 96.6h1.3v.3h-1.3zM41.9 94.1h1.3v.3h-1.3zM41.9 91.6h1.3v.2h-1.3zM41.9 89h1.3v.3h-1.3zM41.9 86.5h1.3v.2h-1.3zM41.9 83.9h1.3v.3h-1.3zM41.9 81.4h1.3v.3h-1.3zM45.7 99.2h1.3v.2h-1.3zM45.7 96.6h1.3v.3h-1.3zM45.7 94.1h1.3v.3h-1.3zM45.7 91.6h1.3v.2h-1.3zM45.7 89h1.3v.3h-1.3z"/>
<path d="M45.7 86.5h1.3v.2h-1.3zM45.7 83.9h1.3v.3h-1.3zM45.7 81.4h1.3v.3h-1.3zM47 89.1h3.8M47 91.7h3.8M47 94.2h3.8M47 96.8h3.8M47 99.3h3.8M47 86.6h3.8M47 84.1h3.8M47 81.5h3.8M53.3 84.1h1.3v1.2l1.3-1.2-1.3-1.3v1.3"/>
<path d="M53.3 91.7h1.3v1.3l1.3-1.3-1.3-1.3v1.3M53.3 99.3h1.3v1.3l1.3-1.3-1.3-1.3v1.3M102.9 99.3h1.2M109.2 99.3h1.3M124.5 84.1v1.2h1.2l-1.2 1.3-1.3-1.3h1.3M124.5 81.5v1.3M127 94.2h5.1M127 99.3h5.1M167.6 98h5.1M167.6 95.5h5.1M167.6 90.4h5.1M167.6 87.9h5.1"/>
<path d="M167.6 82.8h5.1M167.6 80.3h5.1M241.3 86.6v-1.3l-1.3 1.3 1.3 1.3v-1.3h1.3M241.3 94.2v-1.2l-1.3 1.2 1.3 1.3v-1.3h1.3M245.1 89.1h3.8M245.1 91.7h3.8M245.1 94.2h3.8M245.1 96.8h3.8M245.1 99.3h3.8M245.1 86.6h3.8M245.1 84.1h3.8M245.1 81.5h3.8"/>
<path d="M248.9 99.2h1.3v.2h-1.3zM248.9 96.6h1.3v.3h-1.3zM248.9 94.1h1.3v.3h-1.3zM248.9 91.6h1.3v.2h-1.3zM248.9 89h1.3v.3h-1.3zM248.9 86.5h1.3v.2h-1.3zM248.9 83.9h1.3v.3h-1.3zM248.9 81.4h1.3v.3h-1.3zM252.7 99.2h1.3v.2h-1.3zM252.7 96.6h1.3v.3h-1.3zM252.7 94.1h1.3v.3h-1.3zM252.7 91.6h1.3v.2h-1.3z"/>
<path d="M252.7 89h1.3v.3h-1.3zM252.7 86.5h1.3v.2h-1.3zM252.7 83.9h1.3v.3h-1.3zM252.7 81.4h1.3v.3h-1.3zM254 89.1h3.8M254 91.7h3.8M254 94.2h3.8M254 96.8h3.8M254 99.3h3.8M254 86.6h3.8M254 84.1h3.8M254 81.5h3.8"/>
<path d="M260.3 82.8h1.3v1.3l1.3-1.3-1.3-1.3v1.3M260.3 90.4h1.3v1.3l1.3-1.3-1.3-1.3v1.3M260.3 98h1.3v1.3l1.3-1.3-1.3-1.2v1.2M266.7 94.2h2.5M266.7 86.6h2.5M268 85.8l1.2 .8M268 93.5l1.2 .7M269.2 86.6l-1.2 .8M269.2 94.2l-1.2 .8M10 110.3h2M38.1 101.8h3.8M38.1 104.4h3.8"/>
<path d="M38.1 106.9h3.8M38.1 109.5h3.8M38.1 112h3.8M38.1 114.5h3.8M41.9 114.4h1.3v.3h-1.3zM41.9 111.9h1.3v.2h-1.3zM41.9 109.3h1.3v.3h-1.3zM41.9 106.8h1.3v.3h-1.3zM41.9 104.3h1.3v.2h-1.3zM41.9 101.7h1.3v.3h-1.3zM44.4 115.8v5.1M45.7 114.4h1.3v.3h-1.3z"/>
<path d="M45.7 111.9h1.3v.2h-1.3zM45.7 109.3h1.3v.3h-1.3zM45.7 106.8h1.3v.3h-1.3zM45.7 104.3h1.3v.2h-1.3zM45.7 101.7h1.3v.3h-1.3zM47 101.8h3.8M47 104.4h3.8M47 106.9h3.8M47 109.5h3.8M47 112h3.8M47 114.5h3.8M53.3 106.9h1.3v1.3l1.3-1.3-1.3-1.2v1.2"/>
<path d="M53.3 114.5h1.3v1.3l1.3-1.3-1.3-1.2v1.2M102.9 106.9h1.2M102.9 112h1.2M102.9 119.6h1.2M109.2 106.9h1.3M109.2 112h1.3M109.2 119.6h1.3M114.3 103.6v2.1M114.3 116.3v2.1M127 106.9h5.1M127 112h5.1M127 119.6h5.1"/>
<path d="M167.6 118.4h5.1M167.6 113.3h5.1M167.6 110.7h5.1M167.6 105.7h5.1M167.6 103.1h5.1M241.3 101.8v-1.2l-1.3 1.2 1.3 1.3v-1.3h1.3M241.3 109.5v-1.3l-1.3 1.3 1.3 1.2v-1.2h1.3M241.3 117.1v-1.3l-1.3 1.3 1.3 1.3v-1.3h1.3M245.1 101.8h3.8M245.1 104.4h3.8M245.1 106.9h3.8M245.1 109.5h3.8"/>
<path d="M245.1 112h3.8M245.1 114.5h3.8M245.1 117.1h3.8M245.1 119.6h3.8M248.9 119.5h1.3v.3h-1.3zM248.9 117h1.3v.2h-1.3zM248.9 114.4h1.3v.3h-1.3zM248.9 111.9h1.3v.2h-1.3zM248.9 109.3h1.3v.3h-1.3zM248.9 106.8h1.3v.3h-1.3zM248.9 104.3h1.3v.2h-1.3zM248.9 101.7h1.3v.3h-1.3z"/>
<path d="M252.7 119.5h1.3v.3h-1.3zM252.7 117h1.3v.2h-1.3zM252.7 114.4h1.3v.3h-1.3zM252.7 111.9h1.3v.2h-1.3zM252.7 109.3h1.3v.3h-1.3zM252.7 106.8h1.3v.3h-1.3zM252.7 104.3h1.3v.2h-1.3zM252.7 101.7h1.3v.3h-1.3zM254 101.8h3.8M254 104.4h3.8M254 106.9h3.8M254 109.5h3.8"/>
<path d="M254 112h3.8M254 114.5h3.8M254 117.1h3.8M254 119.6h3.8M260.3 105.7h1.3v1.2l1.3-1.2-1.3-1.3v1.3M260.3 113.3h1.3v1.2l1.3-1.2-1.3-1.3v1.3M266.7 101.8h2.5M266.7 109.5h2.5M266.7 117.1h2.5M268 101.1l1.2 .7M268 108.7l1.2 .8M268 116.3l1.2 .8"/>
<path d="M269.2 101.8l-1.2 .8M269.2 109.5l-1.2 .7M269.2 117.1l-1.2 .8M285 110.3h2M44.4 122.2v1.2h-1.2l1.2 1.3 1.3-1.3h-1.3M102.9 124.7h1.2M102.9 132.3h1.2M102.9 137.4h1.2M109.2 124.7h1.3M109.2 132.3h1.3M109.2 137.4h1.3M114.3 129v2.1"/>
<path d="M127 124.7h5.1M127 132.3h5.1M127 137.4h5.1M167.6 136.1h5.1M167.6 133.6h5.1M167.6 128.5h5.1M167.6 126h5.1M167.6 120.9h5.1M241.3 124.7v-1.3l-1.3 1.3 1.3 1.3v-1.3h1.3M241.3 133.6v-1.3l-1.3 1.3 1.3 1.3v-1.3h1.3M245.1 122.2h3.8M245.1 124.7h3.8"/>
<path d="M245.1 127.2h3.8M245.1 129.8h3.8M245.1 132.3h3.8M245.1 134.9h3.8M245.1 137.4h3.8M245.1 139.9h3.8M248.9 139.8h1.3v.3h-1.3zM248.9 137.3h1.3v.2h-1.3zM248.9 134.7h1.3v.3h-1.3zM248.9 132.2h1.3v.3h-1.3zM248.9 129.7h1.3v.2h-1.3zM248.9 127.1h1.3v.3h-1.3z"/>
<path d="M248.9 124.6h1.3v.2h-1.3zM248.9 122h1.3v.3h-1.3zM252.7 139.8h1.3v.3h-1.3zM252.7 137.3h1.3v.2h-1.3zM252.7 134.7h1.3v.3h-1.3zM252.7 132.2h1.3v.3h-1.3zM252.7 129.7h1.3v.2h-1.3zM252.7 127.1h1.3v.3h-1.3zM252.7 124.6h1.3v.2h-1.3zM252.7 122h1.3v.3h-1.3zM254 122.2h3.8M254 124.7h3.8"/>
<path d="M254 127.2h3.8M254 129.8h3.8M254 132.3h3.8M254 134.9h3.8M254 137.4h3.8M254 139.9h3.8M260.3 120.9h1.3v1.3l1.3-1.3-1.3-1.3v1.3M260.3 128.5h1.3v1.3l1.3-1.3-1.3-1.3v1.3M266.7 124.7h2.5M268 123.9l1.2 .8M269.2 124.7l-1.2 .8M102.9 145h1.2"/>
<path d="M109.2 145h1.3M114.3 141.7v2.1M127 145h5.1M127 150.1h5.1M127 152.6h5.1M167.6 141.2h5.1M167.6 143.8h5.1M245.1 142.5h3.8M245.1 145h3.8M245.1 147.6h3.8M245.1 150.1h3.8M245.1 152.6h3.8"/>
<path d="M248.9 152.5h1.3v.3h-1.3zM248.9 150h1.3v.2h-1.3zM248.9 147.4h1.3v.3h-1.3zM248.9 144.9h1.3v.3h-1.3zM248.9 142.4h1.3v.2h-1.3zM251.5 153.9v5.1M252.7 152.5h1.3v.3h-1.3zM252.7 150h1.3v.2h-1.3zM252.7 147.4h1.3v.3h-1.3zM252.7 144.9h1.3v.3h-1.3zM252.7 142.4h1.3v.2h-1.3zM254 142.5h3.8"/>
<path d="M254 145h3.8M254 147.6h3.8M254 150.1h3.8M254 152.6h3.8M260.3 151.4h1.3v1.2l1.3-1.2-1.3-1.3v1.3M10 160.2h2M66 176.8l.8 1.2M66 176.8v2.5M66 176.8l-.7 1.2M141 160.3v5M143.5 160.3v5M146 169.2v1.2h1.3l-1.3 1.3-1.2-1.3h1.2"/>
<path d="M146 160.3v5M148.6 160.3v5M151.1 160.3v5M156.2 160.3v5M157.5 169.2v1.2h1.2l-1.2 1.3-1.3-1.3h1.3M158.7 160.3v5M177 166.3h108v32h-108zM251.5 160.3v1.2h-1.3l1.3 1.3 1.2-1.3h-1.2M285 160.2h2M35.6 189.5v1.2h1.2l-1.2 1.3-1.3-1.3h1.3M38.1 181.9h3.8M38.1 184.4h3.8"/>
<path d="M38.1 186.9h3.8M41.9 186.8h1.3v.3h-1.3zM41.9 184.3h1.3v.2h-1.3zM41.9 181.7h1.3v.3h-1.3zM60 198.3v1.9M66 192v1.3h1.3l-1.3 1.3-1.2-1.3h1.2M68.6 181.9h3.8M68.6 184.4h3.8M68.6 186.9h3.8M72.4 186.8h1.3v.3h-1.3zM72.4 184.3h1.3v.2h-1.3zM72.4 181.7h1.3v.3h-1.3z"/>
<path d="M90.2 183.1h2.5M95.2 185.7v1.2h1.3l-1.3 1.3-1.2-1.3h1.2M102.9 183.1h2.5M107.9 185.7v1.2h1.3l-1.3 1.3-1.2-1.3h1.2M110 198.3v1.9M115.6 183.1h2.5M120.6 185.7v1.2h1.3l-1.3 1.3-1.2-1.3h1.2M128.3 183.1h2.5M133.3 185.7v1.2h1.3l-1.3 1.3-1.2-1.3h1.2M160 198.3v1.9M177 194.8h108M177 191.8h108"/>
<path d="M177 187.8h108M177 181.8h108M186.5 192.5l-.4 1h1M186.8 193v1M187.6 182.3l-1.3 2M191.8 185.7l.2-.1 .4 .1 .1 .9M191.8 185.1v1.5M197 191.8v3M210 198.3v1.9M225.3 196l.1-.1a.37 .37 0 0 1 .6 .1v.8M226.4 195.8h.6M226.7 195.3v1.3l.3 .2"/>
<path d="M227.5 195.8l.1 .9 .3 .1 .3-.1M228.2 195.8v1M228.8 195.8l.4-.5v1.5M228.8 196.8h.9M230.5 196l-.2-.2-.1-.2 .3-.3h.3l.3 .3-.1 .2-.6 .2a.48 .48 0 0 0-.1 .7l.2 .1 .5-.1a.48 .48 0 0 0-.2-.7M231.7 196.7v.1M232.5 195.5l.4-.2a.94 .94 0 0 1 0 1.5l-.5-.3v-.6zM234.2 195.2l-.4 1.1h.9M234.5 195.8v1M235.3 196.7v.1M235.9 195.8l.5-.5v1.5M235.9 196.8h.9"/>
<path d="M260 198.3v1.9M261 191.8v6.5M269.8 195.2l-1.2 2M270.3 195.5l.2-.2h.3l.3 .5-.9 1h.9"/>
<circle cx="89.4" cy="183.1" r=".76"/>
<circle cx="102.1" cy="183.1" r=".76"/>
<circle cx="114.8" cy="183.1" r=".76"/>
<circle cx="127.5" cy="183.1" r=".76"/>
</g>
<g fill="#ffffc2" stroke="#ffffc2" stroke-width=".18">
<path d="M41.9 65h5.1v50.8h-5.1z"/>
<path d="M248.9 52.3h5.1v101.6h-5.1z"/>
<path d="M41.9 180.6h2.5v7.6h-2.5z"/>
<path d="M72.4 180.6h2.5v7.6h-2.5z"/>
</g>
<g fill="none" stroke="#840000" stroke-width=".25">
<path d="M29.2 27.2h5.1v2h-5.1zM70.1 25.6h2v5.1h-2zM70.1 35.8h2v5.1h-2zM242.8 25.6h2.1v5.1h-2.1zM242.8 35.8h2.1v5.1h-2.1zM118.4 54.9h2v5h-2zM123.4 54.9h2.1v5h-2.1zM248.9 52.3h5.1v101.6h-5.1zM41.9 65h5.1v50.8h-5.1zM123.4 76.4h2.1v5.1h-2.1zM104.1 98.3h5.1v2h-5.1zM104.1 105.9h5.1v2h-5.1z"/>
<path d="M104.1 111h5.1v2h-5.1zM104.1 118.6h5.1v2h-5.1zM104.1 123.7h5.1v2h-5.1zM104.1 131.3h5.1v2h-5.1zM104.1 136.4h5.1v2h-5.1zM104.1 144h5.1v2h-5.1zM41.9 180.6h2.5v7.6h-2.5zM72.4 180.6h2.5v7.6h-2.5z"/>
</g>
<g fill="none" stroke="#000" stroke-width=".18">
<path d="M181.2 79.3h1.2M181.5 71.7h1.1M181.5 74.3h1.1M59.6 88.1l.7-.1 .1-.2v-.4l-.3-.1h-.5v1.5M59.6 95.7l.7-.1 .1-.2v-.4l-.3-.1h-.5v1.5M124.8 98.4h1.2M181.2 94.6h1.2M181.5 87h1.1M181.5 89.5h1.1M59.6 103.3l.7-.1 .1-.2v-.3l-.3-.2h-.5v1.6M59.6 110.9h.7l.1-.2v-.4l-.3-.1h-.5v1.5M124.8 106h1.2"/>
<path d="M124.8 111.1h1.2M124.8 118.7h1.2M181.5 120h1.1M181.5 117.4h1.1M182.5 109.8h1.1M182.5 102.2h1.2M124.8 136.5h1.2M124.8 123.8h1.2M124.8 131.4h1.2M181.2 125.1h1.2M181.5 135.2h1.1M181.5 132.7h1.1"/>
<path d="M46.3 145.1v1.2l-.3 .3h-.4M46.3 145.2l-.5-.1-.2 .1v.8a.48 .48 0 0 0 .7 0M49.6 157.1l-.5-.1-.2 .3v.4l.1 .2h.6M50.2 157.1h.1a.37 .37 0 0 1 .6 .1v.8M50.2 156.5v1.5M64.4 151.7h1.2M124.8 144.1h1.2M181.2 140.3h1.2"/>
</g>
<g fill="none" stroke="#008484" stroke-width=".18">
<path d="M213.5 36.6v-1.6l.5 1.1 .5-1.1v1.6M228.4 35v1.1a.51 .51 0 0 1-.5 .5M161.5 74.5a.64 .64 0 0 1 .7 .6 .64 .64 0 0 1-.7 .6zM161.5 71.9a.64 .64 0 0 1 .7 .7 .64 .64 0 0 1-.7 .6zM161.7 79.5a.64 .64 0 0 1 .7 .7 .64 .64 0 0 1-.7 .6zM136.6 99.4h1M161.5 89.7a.64 .64 0 0 1 .7 .6 .64 .64 0 0 1-.7 .7zM161.5 87.2a.64 .64 0 0 1 .7 .6 .64 .64 0 0 1-.7 .6zM161.7 94.8a.64 .64 0 0 1 .7 .6 .64 .64 0 0 1-.7 .7zM136.6 119.7h1M136.6 112.1h1M136.6 107h1"/>
<path d="M160.6 103h.4M160.7 110v1.3h.6M161.2 102.4h-.6v1.3M161.5 117.6a.64 .64 0 0 1 .7 .7 .64 .64 0 0 1-.7 .6zM136.6 137.5h1M136.6 132.4h1M136.6 124.8h1M161.5 135.4a.64 .64 0 0 1 .7 .7 .64 .64 0 0 1-.7 .6zM161.5 132.9a.64 .64 0 0 1 .7 .6 .64 .64 0 0 1-.7 .7zM161.5 120.2a.64 .64 0 0 1 .7 .6 .64 .64 0 0 1-.7 .7zM161.7 125.3a.64 .64 0 0 1 .7 .6 .64 .64 0 0 1-.7 .6zM136.6 145.1h1"/>
<path d="M137 152.7h1M161.7 140.5a.64 .64 0 0 1 .7 .6 .64 .64 0 0 1-.7 .7z"/>
</g>
<path d="M112.8 103.6h3M112.8 116.3h3M112.8 129h3M112.8 141.7h3" fill="none" stroke="#840000" stroke-width=".33"/>
<path d="M112.8 102.6h3M112.8 115.3h3M112.8 128h3M112.8 140.7h3" fill="none" stroke="#840000" stroke-width=".3"/>
<g fill="none" stroke="#840000" stroke-width=".51">
<path d="M20.8 29h4.1M20.8 27.4h4.1M75.4 29h4.1M75.4 27.4h4.1M81.8 29h4.1M81.8 27.4h4.1M103.4 22.6h4M103.4 21.1h4M109.7 22.6h4.1M109.7 21.1h4.1M116.1 22.6h4M116.1 21.1h4"/>
<path d="M122.4 22.6h4.1M122.4 21.1h4.1M128.8 22.6h4M128.8 21.1h4M135.1 22.6h4.1M135.1 21.1h4.1M156.7 26.4h4.1M156.7 24.9h4.1M163.1 26.4h4M163.1 24.9h4M169.4 26.4h4.1M169.4 24.9h4.1"/>
<path d="M175.8 26.4h4M175.8 24.9h4M198.6 29h4.1M198.6 27.4h4.1M232.9 32.8h4.1M232.9 31.2h4.1M248.2 29h4M248.2 27.4h4M264.7 22.6h4M264.7 21.1h4M264.7 39.1h4M264.7 37.6h4"/>
<path d="M271 22.6h4.1M271 21.1h4.1M271 39.1h4.1M271 37.6h4.1M103.4 44.2h4M103.4 42.7h4M109.7 44.2h4.1M109.7 42.7h4.1M128.8 44.2h4M128.8 42.7h4M169.4 44.2h4.1M169.4 42.7h4.1"/>
<path d="M175.8 44.2h4M175.8 42.7h4"/>
</g>
<path d="M244.7 20.1l-.6-.1-.2 .1v.5l.6 .2 .2 .4-.3 .3-.6-.1" fill="none" stroke="#0000c2" stroke-width=".18"/>
<path d="M36.8 146.3h15.3v10.2h-15.3z" fill="none" stroke="#840084" stroke-width=".18"/>
<path d="M50.5 149.3h.8l.8 .8-.8 .8h-.8zM50.5 151.9h.8l.8 .7-.8 .8h-.8z" fill="none" stroke="#848400" stroke-width=".25"/>
<path d="M45.3 151.9a.62 .62 0 0 0-.8 .1 .62 .62 0 0 0-.2 .7 .57 .57 0 0 0 .3 .6 .57 .57 0 0 0 .7-.1" fill="none" stroke="#848400" stroke-width=".18"/>
<g fill="none" stroke="#008400" stroke-width=".18">
<path d="M101.6 16.8h41.9v34.2M105.4 16.8v1.2M111.8 16.8v1.2M118.1 16.8v1.2M124.5 16.8v1.2M130.8 16.8v1.2M137.2 16.8v1.2M256.5 16.8v16.5M264.2 16.8h15.2M266.7 16.8v1.2M273 16.8v1.2M19 23.1h17.8"/>
<path d="M22.9 23.1v1.3M22.9 32v2.5M27.9 23.1v5.1M34.3 23.1v2.5h2.5M36.8 30.7h-2.5v3.8M61 28.2h6.3v5.1h10.2v-1.3M61 30.7h2.5v3.8M69.8 23.1h19.1M71.1 23.1v1.3M71.1 32v2.5M77.5 23.1v1.3M83.8 23.1v1.3"/>
<path d="M83.8 32v2.5M101.6 38.3h41.9M105.4 25.6v1.3M105.4 38.3v1.3M111.8 25.6v1.3M111.8 38.3v1.3M118.1 25.6v1.3M124.5 25.6v1.3M130.8 25.6v1.3M130.8 38.3v1.3M137.2 25.6v1.3M158.7 20.6v1.2"/>
<path d="M158.7 29.5v1.2M165.1 20.6v1.2M165.1 29.5v1.2M171.4 20.6v1.2M171.4 29.5v1.2M171.4 38.3v1.3M177.8 20.6v1.2M177.8 29.5v1.2M177.8 38.3v1.3M184.1 38.3h-25.4v12.7M184.1 20.6h-31.7v29.2M196.8 23.1h12.7"/>
<path d="M200.7 23.1v1.3M200.7 32v1.3M207 23.1v2.5h2.5M207 30.7h2.5M209.5 28.2h-2.5v5.1M232.4 28.2h2.5M232.4 23.1h24.1M232.4 25.6h7.6v7.7h3.8M234.9 35.8v1.3M243.8 23.1v1.3M243.8 32v2.5M250.2 23.1v1.3"/>
<path d="M250.2 32v1.3M264.2 33.3h15.2M266.7 25.6v1.3M266.7 33.3v1.2M273 25.6v1.3M273 33.3v1.2M71.1 42.2v1.2M105.4 47.2v1.3M111.8 47.2v1.3M119.4 53.6v-1.3h5.1v1.3M121.9 51v1.3M130.8 47.2v1.3"/>
<path d="M141 51v-1.2h5v1.2M151.1 51v-1.2h2.6v1.2M171.4 47.2v1.3M177.8 47.2v1.3M242.6 54.9h1.2M243.8 42.2v1.2M245.1 58.7h-62.2v13.9h-10.2M245.1 53.6h-1.3v2.5h1.3M257.8 53.6h1.3v7.6h-1.3M257.8 58.7h1.3M257.8 56.1h1.3M259.1 57.4h1.2"/>
<path d="M266.7 42.2v1.2M273 42.2v1.2M17.8 72.6v6.4h20.3M17.8 76.4h20.3M24.1 73.9h14M24.1 71.4h14M24.1 68.8h14M24.1 66.3h14M50.8 76.4h1.3v2.6h-1.3M50.8 73.9h22.9M50.8 71.4h22.9M50.8 68.8h22.9"/>
<path d="M50.8 66.3h22.9M52.1 77.7h1.2M104.1 73.9h22.9M104.1 71.4h22.9M104.1 68.8h22.9M104.1 66.3h22.9M104.1 63.7h22.9M119.4 61.2v2.5M124.5 61.2v5.1M124.5 73.9v1.3M242.6 79h2.5M242.6 71.4h2.5"/>
<path d="M242.6 63.7h2.5M245.1 76.4h-53.3v14h-19.1M245.1 73.9h-54.6v14h-17.8M245.1 68.8h-57.1v14h-15.3M245.1 66.3h-58.4v14h-14M245.1 61.2h-61v14h-11.4M257.8 79h8.9M257.8 73.9h1.3v2.5h-1.3M257.8 71.4h8.9M257.8 66.3h1.3v2.5h-1.3M257.8 63.7h8.9M259.1 75.2h1.2"/>
<path d="M259.1 67.6h1.2M35.6 98h1.2M36.8 99.3h1.3M36.8 91.7h1.3M36.8 84.1h1.3M36.8 96.8h1.3M36.8 94.2h1.3M36.8 89.1h1.3M36.8 86.6h1.3M38.1 81.5h-1.3v33h1.3M50.8 89.1h45.7v17.8h6.4M50.8 99.3h2.5"/>
<path d="M50.8 86.6h48.3v12.7h3.8M50.8 91.7h2.5M50.8 84.1h2.5M50.8 94.2h41.9v17.8h10.2M50.8 96.8h39.4v22.8h12.7M50.8 81.5h52.1v12.7h24.1M110.5 99.3h16.5M114.3 99.3v1.3M124.5 82.8v1.3M242.6 94.2h2.5M242.6 86.6h2.5M245.1 99.3h-41.9v14h-30.5"/>
<path d="M245.1 91.7h-45.7v14h-26.7M245.1 84.1h-49.5v13.9h-22.9M245.1 96.8h-43.2v13.9h-29.2M245.1 89.1h-47v14h-25.4M245.1 81.5h-50.8v14h-21.6M257.8 96.8h1.3v2.5h-1.3M257.8 89.1h1.3v2.6h-1.3M257.8 81.5h1.3v2.6h-1.3M257.8 94.2h8.9M257.8 86.6h8.9M259.1 98h1.2M259.1 82.8h1.2"/>
<path d="M259.1 90.4h1.2M36.8 106.9h1.3M36.8 112h1.3M36.8 109.5h1.3M36.8 104.4h1.3M36.8 101.8h1.3M50.8 114.5h2.5M50.8 106.9h2.5M50.8 112h26.7v33h25.4M50.8 109.5h29.2v27.9h22.9M50.8 104.4h33v27.9h19.1M50.8 101.8h35.6v22.9h16.5"/>
<path d="M110.5 106.9h16.5M110.5 112h16.5M110.5 119.6h16.5M114.3 105.7v1.2M114.3 112v1.3M114.3 118.4v1.2M242.6 109.5h2.5M242.6 101.8h2.5M242.6 117.1h2.5M245.1 114.5h-34.3v14h-38.1M245.1 106.9h-38.1v14h-34.3M245.1 112h-35.6v14h-36.8"/>
<path d="M245.1 104.4h-39.4v14h-33M245.1 119.6h-31.7v14h-40.7M257.8 112h1.3v2.5h-1.3M257.8 104.4h1.3v2.5h-1.3M257.8 109.5h8.9M257.8 101.8h8.9M257.8 119.6h1.3v2.6h-1.3M257.8 117.1h8.9M259.1 113.3h1.2M259.1 105.7h1.2M44.4 120.9v1.3M110.5 137.4h16.5"/>
<path d="M110.5 124.7h16.5M110.5 132.3h16.5M114.3 124.7v1.3M114.3 131.1v1.2M114.3 137.4v1.3M222.2 137.4h22.9M222.2 139.9h22.9M242.6 124.7h2.5M242.6 133.6h1.2M245.1 132.3h-1.3v2.6h1.3M245.1 129.8h-26.7v14h-45.7M245.1 127.2h-27.9v14h-44.5"/>
<path d="M245.1 122.2h-30.5v13.9h-41.9M257.8 137.4h22.9M257.8 124.7h8.9M257.8 132.3h22.9M257.8 139.9h22.9M257.8 134.9h22.9M257.8 127.2h1.3v2.6h-1.3M259.1 128.5h1.2M259.1 120.9h1.2M52.1 150.1h74.9M52.1 152.6h74.9M110.5 145h16.5"/>
<path d="M114.3 143.8v1.2M222.2 145h22.9M222.2 142.5h22.9M222.2 147.6h22.9M222.2 150.1h22.9M222.2 152.6h22.9M251.5 159v1.3M257.8 145h22.9M257.8 142.5h22.9M257.8 147.6h22.9M257.8 150.1h1.3v2.5h-1.3M259.1 151.4h1.2"/>
<path d="M66 179.3v2.6h2.6M141 165.3v2.6h10.1v-2.6M143.5 165.3v2.6M146 165.3v3.9M148.6 165.3v2.6M156.2 165.3v2.6h2.5v-2.6M157.5 167.9v1.3M20.3 181.9h17.8M20.3 184.4h17.8M38.1 186.9h-2.5v2.6M50.8 186.9h17.8M68.6 184.4h-2.6v7.6"/>
<path d="M92.7 183.1h2.5v2.6M105.4 183.1h2.5v2.6M118.1 183.1h2.5v2.6M130.8 183.1h2.5v2.6"/>
</g>
<g fill="#008400" stroke="#008400" stroke-width=".25">
<circle cx="52.1" cy="77.7" r=".51"/>
<circle cx="36.8" cy="112" r=".51"/>
<circle cx="36.8" cy="109.5" r=".51"/>
<circle cx="36.8" cy="106.9" r=".51"/>
<circle cx="36.8" cy="104.4" r=".51"/>
<circle cx="36.8" cy="101.8" r=".51"/>
<circle cx="36.8" cy="99.3" r=".51"/>
<circle cx="36.8" cy="96.8" r=".51"/>
<circle cx="36.8" cy="94.2" r=".51"/>
<circle cx="36.8" cy="91.7" r=".51"/>
<circle cx="36.8" cy="89.1" r=".51"/>
<circle cx="36.8" cy="86.6" r=".51"/>
<circle cx="36.8" cy="84.1" r=".51"/>
<circle cx="36.8" cy="98" r=".51"/>
<circle cx="17.8" cy="76.4" r=".51"/>
<circle cx="114.3" cy="106.9" r=".51"/>
<circle cx="114.3" cy="99.3" r=".51"/>
<circle cx="114.3" cy="145" r=".51"/>
<circle cx="114.3" cy="137.4" r=".51"/>
<circle cx="114.3" cy="119.6" r=".51"/>
<circle cx="114.3" cy="112" r=".51"/>
<circle cx="114.3" cy="132.3" r=".51"/>
<circle cx="114.3" cy="124.7" r=".51"/>
<circle cx="146.1" cy="167.9" r=".51"/>
<circle cx="143.5" cy="167.9" r=".51"/>
<circle cx="148.6" cy="167.9" r=".51"/>
<circle cx="157.5" cy="167.9" r=".51"/>
<circle cx="119.4" cy="63.7" r=".51"/>
<circle cx="124.5" cy="66.3" r=".51"/>
<circle cx="121.9" cy="52.3" r=".51"/>
<circle cx="124.5" cy="73.9" r=".51"/>
<circle cx="177.8" cy="38.3" r=".51"/>
<circle cx="171.5" cy="38.3" r=".51"/>
<circle cx="177.8" cy="20.6" r=".51"/>
<circle cx="171.5" cy="20.6" r=".51"/>
<circle cx="165.1" cy="20.6" r=".51"/>
<circle cx="158.8" cy="20.6" r=".51"/>
<circle cx="152.4" cy="49.8" r=".51"/>
<circle cx="105.4" cy="38.3" r=".51"/>
<circle cx="111.8" cy="38.3" r=".51"/>
<circle cx="130.8" cy="38.3" r=".51"/>
<circle cx="105.4" cy="16.8" r=".51"/>
<circle cx="111.8" cy="16.8" r=".51"/>
<circle cx="118.1" cy="16.8" r=".51"/>
<circle cx="124.5" cy="16.8" r=".51"/>
<circle cx="130.8" cy="16.8" r=".51"/>
<circle cx="137.2" cy="16.8" r=".51"/>
<circle cx="143.5" cy="49.8" r=".51"/>
<circle cx="143.5" cy="38.3" r=".51"/>
<circle cx="207" cy="30.7" r=".51"/>
<circle cx="207" cy="23.1" r=".51"/>
<circle cx="200.7" cy="23.1" r=".51"/>
<circle cx="243.8" cy="33.3" r=".51"/>
<circle cx="250.2" cy="23.1" r=".51"/>
<circle cx="256.5" cy="23.1" r=".51"/>
<circle cx="266.7" cy="16.8" r=".51"/>
<circle cx="273" cy="16.8" r=".51"/>
<circle cx="266.7" cy="33.3" r=".51"/>
<circle cx="273" cy="33.3" r=".51"/>
<circle cx="243.8" cy="23.1" r=".51"/>
<circle cx="34.3" cy="23.1" r=".51"/>
<circle cx="27.9" cy="23.1" r=".51"/>
<circle cx="22.9" cy="23.1" r=".51"/>
<circle cx="71.1" cy="33.3" r=".51"/>
<circle cx="71.1" cy="23.1" r=".51"/>
<circle cx="77.5" cy="23.1" r=".51"/>
<circle cx="83.8" cy="23.1" r=".51"/>
<circle cx="243.8" cy="54.9" r=".51"/>
<circle cx="259.1" cy="57.4" r=".51"/>
<circle cx="259.1" cy="67.6" r=".51"/>
<circle cx="259.1" cy="75.2" r=".51"/>
<circle cx="259.1" cy="82.8" r=".51"/>
<circle cx="259.1" cy="90.4" r=".51"/>
<circle cx="259.1" cy="98" r=".51"/>
<circle cx="259.1" cy="105.7" r=".51"/>
<circle cx="259.1" cy="113.3" r=".51"/>
<circle cx="259.1" cy="120.9" r=".51"/>
<circle cx="259.1" cy="128.5" r=".51"/>
<circle cx="243.8" cy="133.6" r=".51"/>
<circle cx="259.1" cy="151.4" r=".51"/>
<circle cx="259.1" cy="56.1" r=".51"/>
<circle cx="259.1" cy="58.7" r=".51"/>
</g>
<path d="M95.2 11.7v38.1M190.5 11.7v38.1M95.2 49.8h-83.8M190.5 49.8h95.2" fill="none" stroke="#0000c2" stroke-width=".18" stroke-dasharray=".4 .4"/>
<use href="#words"/>
</svg>
